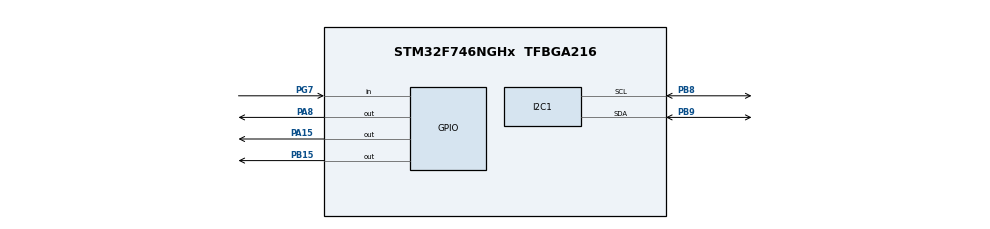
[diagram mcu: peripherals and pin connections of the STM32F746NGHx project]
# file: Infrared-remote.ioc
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I2C1.Timing=0x00C0EAFF
Mcu.Family=STM32F7
Mcu.Name=STM32F746NGHx
Mcu.Package=TFBGA216
NVIC.PriorityGroup=NVIC_PRIORITYGROUP_4
PA13.Mode=Serial_Wire
PA13.Signal=SYS_JTMS-SWDIO
PA14.Mode=Serial_Wire
PA14.Signal=SYS_JTCK-SWCLK
PA15.Signal=GPIO_Output
PA8.Signal=GPIO_Output
PB15.Signal=GPIO_Output
PB8.Mode=I2C
PB8.Signal=I2C1_SCL
PB9.Mode=I2C
PB9.Signal=I2C1_SDA
PG7.Signal=GPIO_Input
PH0/OSC_IN.Mode=HSE-External-Oscillator
PH0/OSC_IN.Signal=RCC_OSC_IN
PH1/OSC_OUT.Mode=HSE-External-Oscillator
PH1/OSC_OUT.Signal=RCC_OSC_OUT
ProjectManager.HeapSize=0x200
ProjectManager.StackSize=0x400
ProjectManager.TargetToolchain=STM32CubeIDE
RCC.AHBCLKDivider=2
RCC.AHBFreq_Value=200000000
RCC.APB1CLKDivider=RCC_HCLK_DIV4
RCC.APB1Freq_Value=50000000
RCC.APB1TimFreq_Value=100000000
RCC.APB2CLKDivider=RCC_HCLK_DIV2
RCC.APB2Freq_Value=100000000
RCC.APB2TimFreq_Value=200000000
RCC.CortexFreq_Value=200000000
RCC.HCLKFreq_Value=200000000
RCC.HSE_VALUE=25000000
RCC.HSI_VALUE=16000000
RCC.PLL48CLockSelection=RCC_CLK48SOURCE_PLLSAIP
RCC.PLLI2SN=100
RCC.PLLQ=9
RCC.PLLSAIN=384
RCC.PLLSAIP=RCC_PLLSAIP_DIV8
RCC.PLLSAIR=5
RCC.PLLSAIRDiv=RCC_PLLSAIDIVR_8
RCC.PLLSourceVirtual=RCC_PLLSOURCE_HSE
RCC.SDMMCClockSelection=RCC_SDMMC1CLKSOURCE_CLK48
RCC.SYSCLKFreq_VALUE=200000000
RCC.SYSCLKSource=RCC_SYSCLKSOURCE_PLLCLK
RCC.USBFreq_Value=48000000
RCC.VCOOutputFreq_Value=400000000
board=STM32F746G-DISCO

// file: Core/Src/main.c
/* USER CODE BEGIN Header */
/**
  ******************************************************************************
  * @file           : main.c
  * @brief          : Main program body
  ******************************************************************************
  * @attention
  *
  * Copyright (c) 2022 STMicroelectronics.
  * All rights reserved.
  *
  * This software is licensed under terms that can be found in the LICENSE file
  * in the root directory of this software component.
  * If no LICENSE file comes with this software, it is provided AS-IS.
  *
  ******************************************************************************
  */
/* USER CODE END Header */
#include "main.h"

/* USER CODE BEGIN Includes */
#include "dwt_stm32_delay.h"
#include "i2c-lcd.h"

/* USER CODE END Includes */

I2C_HandleTypeDef hi2c1;

void SystemClock_Config(void);
static void MX_GPIO_Init(void);
static void MX_I2C1_Init(void);

int main(void)
{
  /* USER CODE BEGIN 1 */
	uint32_t data;
	uint8_t count;

	uint32_t receive_data (void)
	{
		uint32_t code=0;

			  /* The START Sequence begin here
		   * there will be a pulse of 9ms LOW and
		   * than 4.5 ms space (HIGH)
		   */
		  while (!(HAL_GPIO_ReadPin (GPIOG, GPIO_PIN_7)));  // wait for the pin to go high.. 9ms LOW

		  while ((HAL_GPIO_ReadPin (GPIOG, GPIO_PIN_7)));  // wait for the pin to go low.. 4.5ms HIGH

		  /* START of FRAME ends here*/

		  /* DATA Reception
		   * We are only going to check the SPACE after 562.5us pulse
		   * if the space is 562.5us, the bit indicates '0'
		   * if the space is around 1.6ms, the bit is '1'
		   */

		  for (int i=0; i<32; i++)
		  {
			  count=0;

			  while (!(HAL_GPIO_ReadPin (GPIOG, GPIO_PIN_7))); // wait for pin to go high.. this is 562.5us LOW

			  while ((HAL_GPIO_ReadPin (GPIOG, GPIO_PIN_7)))  // count the space length while the pin is high
			  {
				  count++;
				  DWT_Delay_us(100);
			  }

			  if (count > 12) // if the space is more than 1.2 ms
			  {
				  code |= (1UL << (31-i));   // write 1
			  }

			  else code &= ~(1UL << (31-i));  // write 0
		  }

			return code;
	}

	void convert_code (uint32_t code)
	{
			switch (code)
			{
				case (0xFFA25D):
					lcd_send_cmd (0x86);
					lcd_send_data ('1');
					break;

				case (0xFF629D):
					lcd_send_cmd (0x86);
					lcd_send_data ('2');
					break;

				case (0xFFE21D):
					lcd_send_cmd (0x86);
					lcd_send_data ('3');
					break;

				case (0xFF22DD):
					lcd_send_cmd (0x86);
					lcd_send_data ('4');
					break;

				case (0xFF02FD):
					lcd_send_cmd (0x86);
					lcd_send_data ('5');
					break;

				case (0xFFC23D):
					lcd_send_cmd (0x86);
					lcd_send_data ('6');
					break;

				case (0xFFE01F):
					lcd_send_cmd (0x86);
					lcd_send_data ('7');
					break;

				case (0xFFA857):
					lcd_send_cmd (0x86);
					lcd_send_data ('8');
					break;

				case (0xFF906F):
					lcd_send_cmd (0x86);
					lcd_send_data ('9');
					break;

				case (0xFFB04F):
					lcd_send_cmd (0x86);
					lcd_send_data ('#');
					break;

				case (0XFF6897):
					lcd_send_cmd (0x86);
					lcd_send_data ('*');
					break;

				case (0xFF9867):
					lcd_send_cmd (0x86);
					lcd_send_data ('0');
					break;

				case (0xFF38C7):
					lcd_send_cmd (0x86);
					lcd_send_data ('K');
					break;

				case (0xFF18E7):
					lcd_send_cmd (0x86);
					lcd_send_data ('^');
					break;

				case (0xFF10EF):
					lcd_send_cmd (0x86);
					lcd_send_data ('<');
					break;

				case (0xFF5AA5):
					lcd_send_cmd (0x86);
					lcd_send_data ('>');
					break;

				case (0xFF4AB5):
					lcd_send_cmd (0x86);
					lcd_send_data ('u');
					break;

				default :
					break;
			}
	}

  /* USER CODE END 1 */

  /* MCU Configuration--------------------------------------------------------*/

  /* Reset of all peripherals, Initializes the Flash interface and the Systick. */
  HAL_Init();

  /* Configure the system clock */
  SystemClock_Config();

  /* Initialize all configured peripherals */
  MX_GPIO_Init();
  MX_I2C1_Init();
  /* USER CODE BEGIN 2 */
  DWT_Delay_Init ();
  	lcd_init ();

  /* USER CODE END 2 */

  /* Infinite loop */
  while (1)
  {

    /* USER CODE BEGIN 3 */
	  while (HAL_GPIO_ReadPin (GPIOG, GPIO_PIN_7));   // wait for the pin to go low

	 		data = receive_data ();

	 		convert_code (data);

	 		HAL_Delay (200);

  }
  /* USER CODE END 3 */
}

void SystemClock_Config(void)
{
  RCC_OscInitTypeDef RCC_OscInitStruct = {0};
  RCC_ClkInitTypeDef RCC_ClkInitStruct = {0};

  /** Configure the main internal regulator output voltage
  */
  __HAL_RCC_PWR_CLK_ENABLE();
  __HAL_PWR_VOLTAGESCALING_CONFIG(PWR_REGULATOR_VOLTAGE_SCALE1);

  /** Initializes the RCC Oscillators according to the specified parameters
  * in the RCC_OscInitTypeDef structure.
  */
  RCC_OscInitStruct.OscillatorType = RCC_OSCILLATORTYPE_HSE;
  RCC_OscInitStruct.HSEState = RCC_HSE_ON;
  RCC_OscInitStruct.PLL.PLLState = RCC_PLL_ON;
  RCC_OscInitStruct.PLL.PLLSource = RCC_PLLSOURCE_HSE;
  RCC_OscInitStruct.PLL.PLLM = 16;
  RCC_OscInitStruct.PLL.PLLN = 192;
  RCC_OscInitStruct.PLL.PLLP = RCC_PLLP_DIV2;
  RCC_OscInitStruct.PLL.PLLQ = 9;
  if (HAL_RCC_OscConfig(&RCC_OscInitStruct) != HAL_OK)
  {
    Error_Handler();
  }

  /** Activate the Over-Drive mode
  */
  if (HAL_PWREx_EnableOverDrive() != HAL_OK)
  {
    Error_Handler();
  }

  /** Initializes the CPU, AHB and APB buses clocks
  */
  RCC_ClkInitStruct.ClockType = RCC_CLOCKTYPE_HCLK|RCC_CLOCKTYPE_SYSCLK
                              |RCC_CLOCKTYPE_PCLK1|RCC_CLOCKTYPE_PCLK2;
  RCC_ClkInitStruct.SYSCLKSource = RCC_SYSCLKSOURCE_PLLCLK;
  RCC_ClkInitStruct.AHBCLKDivider = 2;
  RCC_ClkInitStruct.APB1CLKDivider = RCC_HCLK_DIV4;
  RCC_ClkInitStruct.APB2CLKDivider = RCC_HCLK_DIV2;

  if (HAL_RCC_ClockConfig(&RCC_ClkInitStruct, FLASH_LATENCY_6) != HAL_OK)
  {
    Error_Handler();
  }
}

static void MX_I2C1_Init(void)
{

  hi2c1.Instance = I2C1;
  hi2c1.Init.Timing = 0x00C0EAFF;
  hi2c1.Init.OwnAddress1 = 0;
  hi2c1.Init.AddressingMode = I2C_ADDRESSINGMODE_7BIT;
  hi2c1.Init.DualAddressMode = I2C_DUALADDRESS_DISABLE;
  hi2c1.Init.OwnAddress2 = 0;
  hi2c1.Init.OwnAddress2Masks = I2C_OA2_NOMASK;
  hi2c1.Init.GeneralCallMode = I2C_GENERALCALL_DISABLE;
  hi2c1.Init.NoStretchMode = I2C_NOSTRETCH_DISABLE;
  if (HAL_I2C_Init(&hi2c1) != HAL_OK)
  {
    Error_Handler();
  }

  /** Configure Analogue filter
  */
  if (HAL_I2CEx_ConfigAnalogFilter(&hi2c1, I2C_ANALOGFILTER_ENABLE) != HAL_OK)
  {
    Error_Handler();
  }

  /** Configure Digital filter
  */
  if (HAL_I2CEx_ConfigDigitalFilter(&hi2c1, 0) != HAL_OK)
  {
    Error_Handler();
  }

}

static void MX_GPIO_Init(void)
{
  GPIO_InitTypeDef GPIO_InitStruct = {0};

  /* GPIO Ports Clock Enable */
  __HAL_RCC_GPIOB_CLK_ENABLE();
  __HAL_RCC_GPIOA_CLK_ENABLE();
  __HAL_RCC_GPIOH_CLK_ENABLE();
  __HAL_RCC_GPIOG_CLK_ENABLE();

  /*Configure GPIO pin Output Level */
  HAL_GPIO_WritePin(GPIOA, GPIO_PIN_15|GPIO_PIN_8, GPIO_PIN_RESET);

  /*Configure GPIO pin Output Level */
  HAL_GPIO_WritePin(GPIOB, GPIO_PIN_15, GPIO_PIN_RESET);

  /*Configure GPIO pins : PA15 PA8 */
  GPIO_InitStruct.Pin = GPIO_PIN_15|GPIO_PIN_8;
  GPIO_InitStruct.Mode = GPIO_MODE_OUTPUT_PP;
  GPIO_InitStruct.Pull = GPIO_NOPULL;
  GPIO_InitStruct.Speed = GPIO_SPEED_FREQ_LOW;
  HAL_GPIO_Init(GPIOA, &GPIO_InitStruct);

  /*Configure GPIO pin : PG7 */
  GPIO_InitStruct.Pin = GPIO_PIN_7;
  GPIO_InitStruct.Mode = GPIO_MODE_INPUT;
  GPIO_InitStruct.Pull = GPIO_NOPULL;
  HAL_GPIO_Init(GPIOG, &GPIO_InitStruct);

  /*Configure GPIO pin : PB15 */
  GPIO_InitStruct.Pin = GPIO_PIN_15;
  GPIO_InitStruct.Mode = GPIO_MODE_OUTPUT_PP;
  GPIO_InitStruct.Pull = GPIO_NOPULL;
  GPIO_InitStruct.Speed = GPIO_SPEED_FREQ_LOW;
  HAL_GPIO_Init(GPIOB, &GPIO_InitStruct);

}

void Error_Handler(void)
{
  __disable_irq();
  while (1)
  {
  }
}
